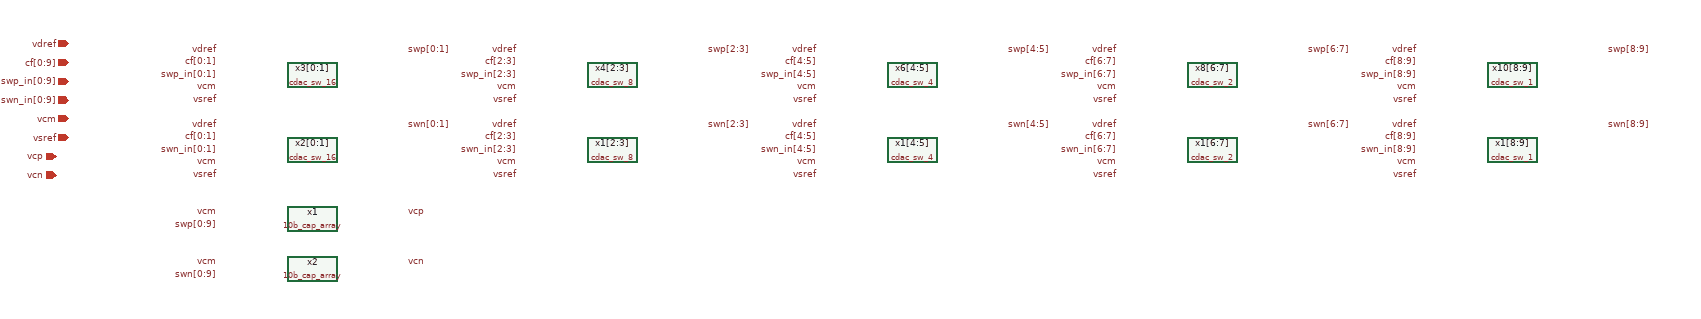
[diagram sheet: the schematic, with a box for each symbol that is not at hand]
v {xschem version=3.4.5 file_version=1.2
}
G {}
K {}
V {}
S {}
E {}
C {10b_cap_array.sym} 570 -340 0 0 {name=x1}
C {cdac_sw_16.sym} 570 -450 0 0 {name=x2[0:1]}
C {cdac_sw_16.sym} 570 -570 0 0 {name=x3[0:1]}
C {devices/lab_wire.sym} 420 -610 0 0 {name=p1 sig_type=std_logic lab=vdref}
C {devices/lab_wire.sym} 420 -490 0 0 {name=p2 sig_type=std_logic lab=vdref}
C {devices/lab_wire.sym} 420 -530 0 0 {name=p3 sig_type=std_logic lab=vsref}
C {devices/lab_wire.sym} 420 -410 0 0 {name=p4 sig_type=std_logic lab=vsref}
C {devices/lab_wire.sym} 720 -610 2 0 {name=p5 sig_type=std_logic lab=swp[0:1]}
C {devices/lab_wire.sym} 420 -330 0 0 {name=p6 sig_type=std_logic lab=swp[0:9]}
C {devices/lab_wire.sym} 720 -490 2 0 {name=p7 sig_type=std_logic lab=swn[0:1]}
C {devices/lab_wire.sym} 420 -250 0 0 {name=p8 sig_type=std_logic lab=swn[0:9]}
C {devices/lab_wire.sym} 420 -350 0 0 {name=p9 sig_type=std_logic lab=vcm}
C {devices/lab_wire.sym} 420 -430 0 0 {name=p10 sig_type=std_logic lab=vcm}
C {devices/lab_wire.sym} 420 -550 0 0 {name=p11 sig_type=std_logic lab=vcm}
C {devices/lab_wire.sym} 420 -590 0 0 {name=p12 sig_type=std_logic lab=cf[0:1]}
C {devices/lab_wire.sym} 420 -470 0 0 {name=p13 sig_type=std_logic lab=cf[0:1]}
C {devices/lab_wire.sym} 420 -570 0 0 {name=p14 sig_type=std_logic lab=swp_in[0:1]}
C {devices/lab_wire.sym} 420 -450 0 0 {name=p15 sig_type=std_logic lab=swn_in[0:1]}
C {devices/lab_wire.sym} 720 -350 0 1 {name=p16 sig_type=std_logic lab=vcp}
C {devices/lab_wire.sym} 720 -270 0 1 {name=p17 sig_type=std_logic lab=vcn}
C {devices/ipin.sym} 180 -620 0 0 {name=p18 lab=vdref}
C {devices/ipin.sym} 180 -590 0 0 {name=p19 lab=cf[0:9]}
C {devices/ipin.sym} 180 -560 0 0 {name=p20 lab=swp_in[0:9]}
C {devices/ipin.sym} 180 -530 0 0 {name=p21 lab=swn_in[0:9]}
C {devices/ipin.sym} 180 -500 0 0 {name=p22 lab=vcm}
C {devices/ipin.sym} 180 -470 0 0 {name=p23 lab=vsref}
C {devices/iopin.sym} 160 -440 0 0 {name=p24 lab=vcp}
C {devices/iopin.sym} 160 -410 0 0 {name=p25 lab=vcn}
C {10b_cap_array.sym} 570 -260 0 0 {name=x2}
C {devices/lab_wire.sym} 420 -270 0 0 {name=p27 sig_type=std_logic lab=vcm}
C {cdac_sw_8.sym} 1050 -450 0 0 {name=x1[2:3]}
C {cdac_sw_8.sym} 1050 -570 0 0 {name=x4[2:3]}
C {devices/lab_wire.sym} 900 -610 0 0 {name=p26 sig_type=std_logic lab=vdref}
C {devices/lab_wire.sym} 900 -490 0 0 {name=p28 sig_type=std_logic lab=vdref}
C {devices/lab_wire.sym} 900 -530 0 0 {name=p29 sig_type=std_logic lab=vsref}
C {devices/lab_wire.sym} 900 -410 0 0 {name=p30 sig_type=std_logic lab=vsref}
C {devices/lab_wire.sym} 1200 -610 2 0 {name=p31 sig_type=std_logic lab=swp[2:3]}
C {devices/lab_wire.sym} 1200 -490 2 0 {name=p32 sig_type=std_logic lab=swn[2:3]}
C {devices/lab_wire.sym} 900 -430 0 0 {name=p33 sig_type=std_logic lab=vcm}
C {devices/lab_wire.sym} 900 -550 0 0 {name=p34 sig_type=std_logic lab=vcm}
C {devices/lab_wire.sym} 900 -590 0 0 {name=p35 sig_type=std_logic lab=cf[2:3]}
C {devices/lab_wire.sym} 900 -470 0 0 {name=p36 sig_type=std_logic lab=cf[2:3]}
C {devices/lab_wire.sym} 900 -570 0 0 {name=p37 sig_type=std_logic lab=swp_in[2:3]}
C {devices/lab_wire.sym} 900 -450 0 0 {name=p38 sig_type=std_logic lab=swn_in[2:3]}
C {cdac_sw_4.sym} 1530 -450 0 0 {name=x1[4:5]}
C {cdac_sw_4.sym} 1530 -570 0 0 {name=x6[4:5]}
C {devices/lab_wire.sym} 1380 -610 0 0 {name=p39 sig_type=std_logic lab=vdref}
C {devices/lab_wire.sym} 1380 -490 0 0 {name=p40 sig_type=std_logic lab=vdref}
C {devices/lab_wire.sym} 1380 -530 0 0 {name=p41 sig_type=std_logic lab=vsref}
C {devices/lab_wire.sym} 1380 -410 0 0 {name=p42 sig_type=std_logic lab=vsref}
C {devices/lab_wire.sym} 1680 -610 2 0 {name=p43 sig_type=std_logic lab=swp[4:5]}
C {devices/lab_wire.sym} 1680 -490 2 0 {name=p44 sig_type=std_logic lab=swn[4:5]}
C {devices/lab_wire.sym} 1380 -430 0 0 {name=p45 sig_type=std_logic lab=vcm}
C {devices/lab_wire.sym} 1380 -550 0 0 {name=p46 sig_type=std_logic lab=vcm}
C {devices/lab_wire.sym} 1380 -590 0 0 {name=p47 sig_type=std_logic lab=cf[4:5]}
C {devices/lab_wire.sym} 1380 -470 0 0 {name=p48 sig_type=std_logic lab=cf[4:5]}
C {devices/lab_wire.sym} 1380 -570 0 0 {name=p49 sig_type=std_logic lab=swp_in[4:5]}
C {devices/lab_wire.sym} 1380 -450 0 0 {name=p50 sig_type=std_logic lab=swn_in[4:5]}
C {cdac_sw_2.sym} 2010 -450 0 0 {name=x1[6:7]}
C {cdac_sw_2.sym} 2010 -570 0 0 {name=x8[6:7]}
C {devices/lab_wire.sym} 1860 -610 0 0 {name=p51 sig_type=std_logic lab=vdref}
C {devices/lab_wire.sym} 1860 -490 0 0 {name=p52 sig_type=std_logic lab=vdref}
C {devices/lab_wire.sym} 1860 -530 0 0 {name=p53 sig_type=std_logic lab=vsref}
C {devices/lab_wire.sym} 1860 -410 0 0 {name=p54 sig_type=std_logic lab=vsref}
C {devices/lab_wire.sym} 2160 -610 2 0 {name=p55 sig_type=std_logic lab=swp[6:7]}
C {devices/lab_wire.sym} 2160 -490 2 0 {name=p56 sig_type=std_logic lab=swn[6:7]}
C {devices/lab_wire.sym} 1860 -430 0 0 {name=p57 sig_type=std_logic lab=vcm}
C {devices/lab_wire.sym} 1860 -550 0 0 {name=p58 sig_type=std_logic lab=vcm}
C {devices/lab_wire.sym} 1860 -590 0 0 {name=p59 sig_type=std_logic lab=cf[6:7]}
C {devices/lab_wire.sym} 1860 -470 0 0 {name=p60 sig_type=std_logic lab=cf[6:7]}
C {devices/lab_wire.sym} 1860 -570 0 0 {name=p61 sig_type=std_logic lab=swp_in[6:7]}
C {devices/lab_wire.sym} 1860 -450 0 0 {name=p62 sig_type=std_logic lab=swn_in[6:7]}
C {cdac_sw_1.sym} 2490 -450 0 0 {name=x1[8:9]}
C {cdac_sw_1.sym} 2490 -570 0 0 {name=x10[8:9]}
C {devices/lab_wire.sym} 2340 -610 0 0 {name=p63 sig_type=std_logic lab=vdref}
C {devices/lab_wire.sym} 2340 -490 0 0 {name=p64 sig_type=std_logic lab=vdref}
C {devices/lab_wire.sym} 2340 -530 0 0 {name=p65 sig_type=std_logic lab=vsref}
C {devices/lab_wire.sym} 2340 -410 0 0 {name=p66 sig_type=std_logic lab=vsref}
C {devices/lab_wire.sym} 2640 -610 2 0 {name=p67 sig_type=std_logic lab=swp[8:9]}
C {devices/lab_wire.sym} 2640 -490 2 0 {name=p68 sig_type=std_logic lab=swn[8:9]}
C {devices/lab_wire.sym} 2340 -430 0 0 {name=p69 sig_type=std_logic lab=vcm}
C {devices/lab_wire.sym} 2340 -550 0 0 {name=p70 sig_type=std_logic lab=vcm}
C {devices/lab_wire.sym} 2340 -590 0 0 {name=p71 sig_type=std_logic lab=cf[8:9]}
C {devices/lab_wire.sym} 2340 -470 0 0 {name=p72 sig_type=std_logic lab=cf[8:9]}
C {devices/lab_wire.sym} 2340 -570 0 0 {name=p73 sig_type=std_logic lab=swp_in[8:9]}
C {devices/lab_wire.sym} 2340 -450 0 0 {name=p74 sig_type=std_logic lab=swn_in[8:9]}
